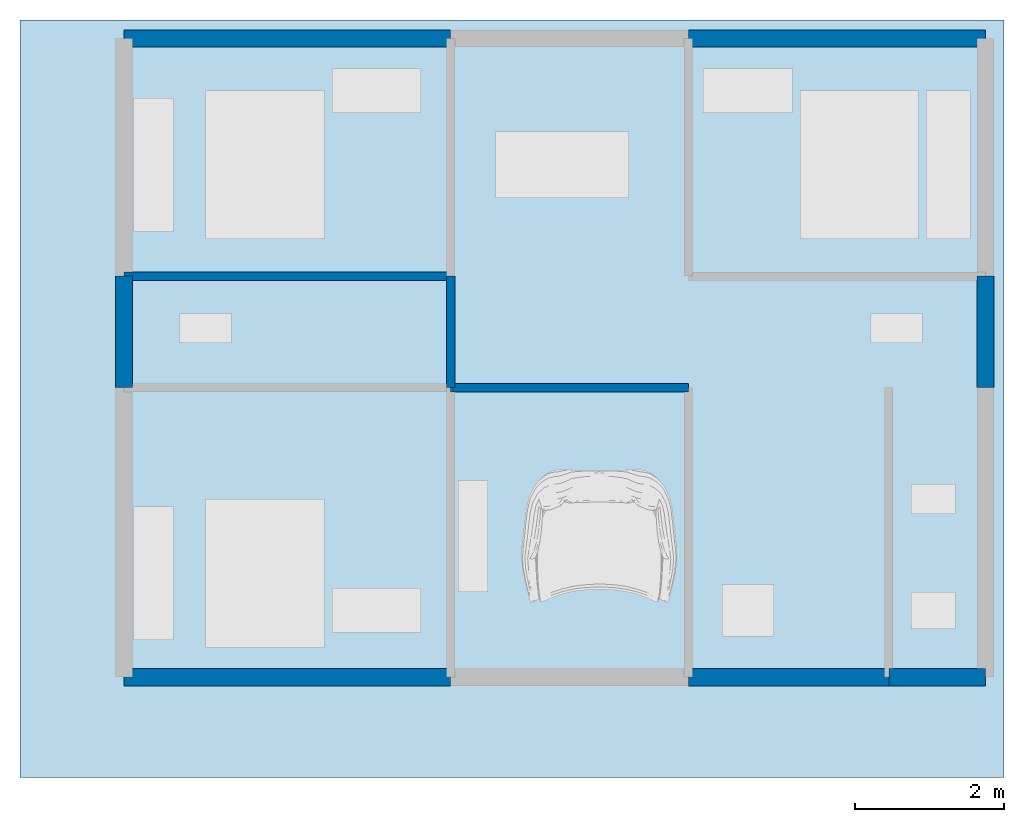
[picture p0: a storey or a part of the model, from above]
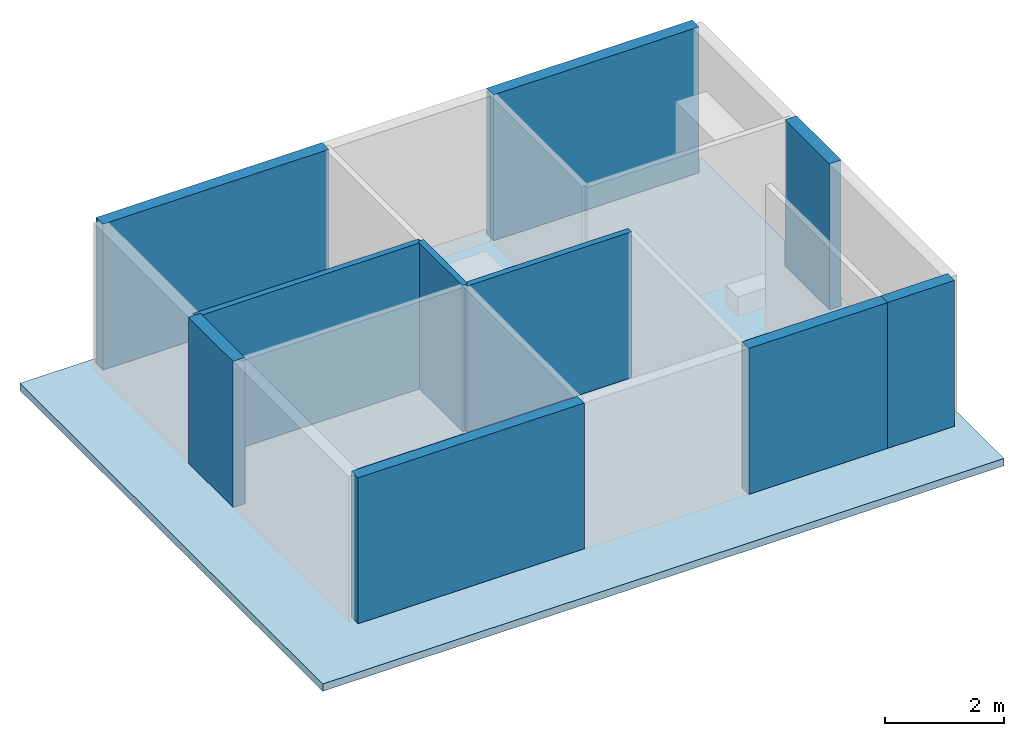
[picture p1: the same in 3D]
Properties of the parts of a building model (IFC4)

# File
Description: ViewDefinition [CoordinationView]
Time: 2026-06-09T21:56:07
Written by: IfcOpenShell 0.8.4-e8eb5e4
Made in: IfcOpenShell 0.8.4-e8eb5e4

# IfcDoor (9)
In: Ground Floor
OverallHeight: 2.1 m; PredefinedType: DOOR
Pset_DoorCommon - OperationType: SINGLE_SWING_RIGHT; OverallHeight: 2.1 m; Finish: Painted; IsExternal: no; SecurityRating: Medium; DoorLeafs: 1; ThresholdHeight: 0.05 m; IsAccessible: yes
Name | OverallWidth (m) = Pset_DoorCommon, OverallWidth (m) | OperationType | Material = Pset_DoorCommon, Material | Color
d_ent | 1 | SINGLE_SWING_RIGHT | Wood | #66331A
d_mb | 0.9 | SINGLE_SWING_LEFT | Wood | #804C1A
d_b1 | 0.9 | SINGLE_SWING_RIGHT | Wood | #804C1A
d_b2 | 0.9 | SINGLE_SWING_LEFT | Wood | #804C1A
d_t1 | 0.75 | SINGLE_SWING_RIGHT | Wood | #804C1A
d_t2 | 0.75 | SINGLE_SWING_LEFT | Wood | #804C1A
d_kit | 0.9 | SINGLE_SWING_RIGHT | Wood | #804C1A
d_util | 0.75 | SINGLE_SWING_RIGHT | Wood | #804C1A
d_bal | 1.8 | SLIDING_TO_RIGHT | Aluminium/Glass | #CCCCE6

# IfcElectricAppliance (2)
In: Ground Floor
Pset_ElectricApplianceTypeCommon - PowerRating: 1000; Voltage: 230; Manufacturer: LG; ModelNumber: Standard Model; EnergyRating: 3 Star
Name | PredefinedType = ApplianceType | Material = Pset_ElectricApplianceTypeCommon, Material | Color | OverallWidth (m) | OverallDepth (m) | OverallHeight (m)
int_kit_stove | ELECTRICCOOKER | Glass/Steel | #333333 | 0.6 | 0.4 | 0.15 | Pset_GasStoveTypeCommon - BurnerCount: 4; FuelType: LPG; StoveType: Glass Top; AutoIgnition: yes; HasGrids: yes
int_kit_fridge | REFRIGERATOR | Steel | #E6E6E6 | 0.7 | 0.7 | 1.7 | Pset_ElectricApplianceTypeCommon - RefrigeratorType: Double Door; Pset_RefrigeratorTypeCommon - RefrigeratorType: Double Door; TotalCapacity: 310; FreezerCapacity: 80; FreshFoodCapacity: 230; InverterCompressor: yes; HasWaterDispenser: no; AnnualPowerConsumption: 250

# IfcFurniture (12)
In: Ground Floor
Pset_FurnitureTypeCommon - Style: Modern; Finish: Laminate; Manufacturer: Urban Ladder; ModelNumber: Standard; Weight: 50; WarrantyYears: 2; AssemblyRequired: no
Name | PredefinedType = FurnitureType | Material = Pset_FurnitureTypeCommon, Material | Color | OverallWidth (m) | OverallDepth (m) | OverallHeight (m)
int_mb_bed | BED | Wood | #804C1A | 1.6 | 2 | 0.5 | Pset_BedTypeCommon - BedSize: Queen (150x190); StorageType: Hydraulic Box; HasHeadboard: yes; HeadboardMaterial: Teak Wood; MattressIncluded: no; MattressType: Orthopedic; BedFrameMaterial: Teak Wood; IsFolding: no
int_b1_bed | BED | Wood | #804C1A | 1.6 | 2 | 0.5 | Pset_BedTypeCommon - BedSize: Queen (150x190); StorageType: Hydraulic Box; HasHeadboard: yes; HeadboardMaterial: Teak Wood; MattressIncluded: no; MattressType: Orthopedic; BedFrameMaterial: Teak Wood; IsFolding: no
int_b2_bed | BED | Wood | #804C1A | 1.6 | 2 | 0.5 | Pset_BedTypeCommon - BedSize: Queen (150x190); StorageType: Hydraulic Box; HasHeadboard: yes; HeadboardMaterial: Teak Wood; MattressIncluded: no; MattressType: Orthopedic; BedFrameMaterial: Teak Wood; IsFolding: no
int_liv_sofa | SOFA | Fabric | #B2B2B2 | 2.1 | 1.8 | 0.85 | Pset_SofaTypeCommon - SeatingCapacity: 3; SofaConfiguration: L-Shape; UpholsteryMaterial: Fabric; UpholsteryColor: Grey; FrameMaterial: Solid Wood; CushionFilling: High Density Foam; HasSleepFunction: no; HasStorage: no; LegMaterial: Wood
int_din_tab | TABLE | Wood | #66331A | 1.8 | 0.9 | 0.76 | Pset_TableTypeCommon - TableShape: Rectangular; SeatingCapacity: 6; TabletopMaterial: Teak Wood; LegMaterial: Wood; IsExtendable: no
int_mb_ward | SHELF | MDF | #CCB299 | 0.6 | 2 | 2.1 | Pset_CabinetTypeCommon - NumberOfShelves: 3; NumberOfDoors: 2; DoorType: Sliding; CableManagement: no; MountingType: Floor-mounted; HasMirror: no; HasLock: no; InteriorFinish: Laminate; Pset_WardrobeTypeCommon - NumberOfDoors: 3; DoorType: Sliding; HasMirror: yes; InternalLayout: With Drawers; NumberOfShelves: 4; NumberOfDrawers: 2; HasHangingRod: yes; LockType: Handle Lock; BodyMaterial: MDF
int_b1_ward | SHELF | MDF | #CCB299 | 0.6 | 2 | 2.1 | Pset_CabinetTypeCommon - NumberOfShelves: 3; NumberOfDoors: 2; DoorType: Sliding; CableManagement: no; MountingType: Floor-mounted; HasMirror: no; HasLock: no; InteriorFinish: Laminate; Pset_WardrobeTypeCommon - NumberOfDoors: 3; DoorType: Sliding; HasMirror: yes; InternalLayout: With Drawers; NumberOfShelves: 4; NumberOfDrawers: 2; HasHangingRod: yes; LockType: Handle Lock; BodyMaterial: MDF
int_b2_ward | SHELF | MDF | #CCB299 | 0.6 | 2 | 2.1 | Pset_CabinetTypeCommon - NumberOfShelves: 3; NumberOfDoors: 2; DoorType: Sliding; CableManagement: no; MountingType: Floor-mounted; HasMirror: no; HasLock: no; InteriorFinish: Laminate; Pset_WardrobeTypeCommon - NumberOfDoors: 3; DoorType: Sliding; HasMirror: yes; InternalLayout: With Drawers; NumberOfShelves: 4; NumberOfDrawers: 2; HasHangingRod: yes; LockType: Handle Lock; BodyMaterial: MDF
int_mb_desk | DESK | Wood | #804C1A | 1.2 | 0.6 | 0.75 | Pset_TableTypeCommon - TableShape: Rectangular; SeatingCapacity: 4; TabletopMaterial: Teak Wood; LegMaterial: Wood; IsExtendable: no
int_b1_desk | DESK | Wood | #804C1A | 1.2 | 0.6 | 0.75 | Pset_TableTypeCommon - TableShape: Rectangular; SeatingCapacity: 4; TabletopMaterial: Teak Wood; LegMaterial: Wood; IsExtendable: no
int_b2_desk | DESK | Wood | #804C1A | 1.2 | 0.6 | 0.75 | Pset_TableTypeCommon - TableShape: Rectangular; SeatingCapacity: 4; TabletopMaterial: Teak Wood; LegMaterial: Wood; IsExtendable: no
int_tv_unit | SHELF | Wood | #4C331A | 0.4 | 1.5 | 0.5 | Pset_CabinetTypeCommon - NumberOfShelves: 3; NumberOfDoors: 2; DoorType: Sliding; CableManagement: no; MountingType: Floor-mounted; HasMirror: no; HasLock: no; InteriorFinish: Laminate; Pset_WardrobeTypeCommon - NumberOfDoors: 3; DoorType: Sliding; HasMirror: yes; InternalLayout: With Drawers; NumberOfShelves: 4; NumberOfDrawers: 2; HasHangingRod: yes; LockType: Handle Lock; BodyMaterial: MDF; Pset_TVUnitTypeCommon - TVSizeCompatible: Up to 55 inch; NumberOfShelves: 2; HasCableManagement: yes; HasDrawers: yes; WallMounted: no; FinishMaterial: High Gloss White

# IfcSanitaryTerminal (3)
In: Ground Floor
Pset_SanitaryTerminalTypeCommon - Mounting: Wall-hung; MountingType: Wall-hung; FlushType: Dual Flush; SpigotPosition: Back; BowlCount: 1; HasDrainer: no; TrayMaterial: Acrylic; DrainDiameter: 0.05 m; WaterCapacity: 150; Shape: Built-in; WaterResistance: High; Manufacturer: Jaquar; InstallationHeight: 0.85 m
Name | PredefinedType = SanitaryTerminalType | Material = Pset_SanitaryTerminalTypeCommon, Material | Color | OverallWidth (m) | OverallDepth (m) | OverallHeight (m)
int_t1_wc | TOILETPAN | Ceramic | #FFFFFF | 0.7 | 0.4 | 0.4
int_t2_wc | TOILETPAN | Ceramic | #FFFFFF | 0.7 | 0.4 | 0.4
int_kit_sink | SINK | Stainless Steel | #CCCCCC | 0.6 | 0.5 | 0.2

# IfcSlab, slab_ground
In: Ground Floor
PredefinedType: FLOOR; Material: RCC
Pset_SlabCommon - Material: RCC; Thickness: 150 m; Finish: Smooth; IsExternal: no; LoadBearing: yes

# IfcWallStandardCase (23)
In: Ground Floor
Pset_WallCommon - Material: Brick; Height: 3 m; OverallHeight: 3 m; IsExternal: no; LoadBearing: yes; Finish: Plaster
BaseQuantities - Height: 3 m
ArchiCADQuantities - Höhe: 3 m; Maximale Höhe der Wand: 3 m; Minimale Höhe der Wand: 3 m
Name | Thickness (m) = Pset_WallCommon, Width (m) = OverallWidth (m) = BaseQuantities, Width (m) = Dicke (m) | Length (m) = Länge der Wand in der Achse (m) | GrossFootprintArea (m) = NetFootprintArea (m) = Fläche (m) | GrossVolume (m) = NetVolume (m) = Netto-Volumen (m) | Name | Wandlänge an der Außenseite (m) | Wandlänge an der Innenseite (m)
ext_left_1 | 0.23 | 3.9 | 0.897 | 2.691 | ext_left_1 | 4.13 | 3.67
ext_left_2 | 0.23 | 1.5 | 0.345 | 1.035 | ext_left_2 | 1.73 | 1.27
ext_left_3 | 0.23 | 3.2 | 0.736 | 2.208 | ext_left_3 | 3.43 | 2.97
ext_top_1 | 0.23 | 4.4 | 1.012 | 3.036 | ext_top_1 | 4.63 | 4.17
ext_top_2 | 0.23 | 3.2 | 0.736 | 2.208 | ext_top_2 | 3.43 | 2.97
ext_top_3 | 0.23 | 4 | 0.92 | 2.76 | ext_top_3 | 4.23 | 3.77
ext_right_1 | 0.23 | 3.2 | 0.736 | 2.208 | ext_right_1 | 3.43 | 2.97
ext_right_2 | 0.23 | 1.5 | 0.345 | 1.035 | ext_right_2 | 1.73 | 1.27
ext_right_3 | 0.23 | 3.9 | 0.897 | 2.691 | ext_right_3 | 4.13 | 3.67
ext_bottom_1 | 0.23 | 4.4 | 1.012 | 3.036 | ext_bottom_1 | 4.63 | 4.17
ext_bottom_2 | 0.23 | 3.2 | 0.736 | 2.208 | ext_bottom_2 | 3.43 | 2.97
ext_bottom_3 | 0.23 | 2.7 | 0.621 | 1.863 | ext_bottom_3 | 2.93 | 2.47
ext_bottom_4 | 0.23 | 1.3 | 0.299 | 0.897 | ext_bottom_4 | 1.53 | 1.07
int_mb_liv | 0.115 | 3.9 | 0.4485 | 1.3455 | int_mb_liv | 4.015 | 3.785
int_mb_toilet | 0.115 | 4.4 | 0.506 | 1.518 | int_mb_toilet | 4.515 | 4.285
int_toilet_b1 | 0.115 | 4.4 | 0.506 | 1.518 | int_toilet_b1 | 4.515 | 4.285
int_b1_din | 0.115 | 3.2 | 0.368 | 1.104 | int_b1_din | 3.315 | 3.085
int_din_b2 | 0.115 | 3.2 | 0.368 | 1.104 | int_din_b2 | 3.315 | 3.085
int_b2_toilet2 | 0.115 | 4 | 0.46 | 1.38 | int_b2_toilet2 | 4.115 | 3.885
int_liv_kit | 0.115 | 3.9 | 0.4485 | 1.3455 | int_liv_kit | 4.015 | 3.785
int_kit_util | 0.115 | 3.9 | 0.4485 | 1.3455 | int_kit_util | 4.015 | 3.785
int_pooja_din | 0.115 | 1.5 | 0.1725 | 0.5175 | int_pooja_din | 1.615 | 1.385
int_liv_din_beam | 0.115 | 3.2 | 0.368 | 1.104 | int_liv_din_beam | 3.315 | 3.085

# IfcWindow (5)
In: Ground Floor
PredefinedType: WINDOW; PartitioningType: DOUBLE_PANEL_HORIZONTAL; Material: Aluminium/Glass
Pset_WindowCommon - OperationType: SLIDING; Material: Aluminium/Glass; FrameMaterial: Aluminium; GlazingType: Double; ThermalTransmittance: 3; UValue: 2.5; CillHeight: 0.9 m; IsExternal: yes; Color: #CCCCE6
Name | OverallHeight (m) = Pset_WindowCommon, OverallHeight (m) | OverallWidth (m) = Pset_WindowCommon, OverallWidth (m)
w_mb | 1.2 | 1.5
w_b1 | 1.2 | 1.5
w_b2 | 1.2 | 1.5
w_kit | 1 | 1.2
w_util | 1 | 0.9
